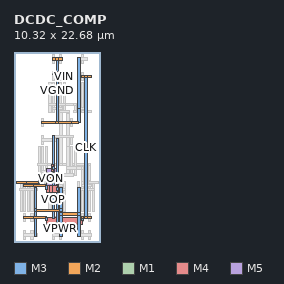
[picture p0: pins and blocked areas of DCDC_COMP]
MACRO DCDC_COMP
  ORIGIN 0 0 ;
  FOREIGN DCDC_COMP 0 0 ;
  SIZE 10.32 BY 22.68 ;
  PIN VOP
    DIRECTION INOUT ;
    USE SIGNAL ;
    PORT
      LAYER M3 ;
        RECT 4.59 2.78 4.87 7.3 ;
      LAYER M2 ;
        RECT 0.26 7 1.46 7.28 ;
      LAYER M3 ;
        RECT 5.02 7.82 5.3 12.34 ;
      LAYER M3 ;
        RECT 4.59 7.14 4.87 7.56 ;
      LAYER M2 ;
        RECT 3.01 7.42 4.73 7.7 ;
      LAYER M1 ;
        RECT 2.885 7.14 3.135 7.56 ;
      LAYER M2 ;
        RECT 1.29 7 3.01 7.28 ;
      LAYER M3 ;
        RECT 4.59 7.375 4.87 7.745 ;
      LAYER M4 ;
        RECT 4.73 7.16 5.16 7.96 ;
      LAYER M3 ;
        RECT 5.02 7.56 5.3 7.98 ;
    END
  END VOP
  PIN VON
    DIRECTION INOUT ;
    USE SIGNAL ;
    PORT
      LAYER M3 ;
        RECT 5.02 2.36 5.3 6.88 ;
      LAYER M2 ;
        RECT 1.12 6.58 2.32 6.86 ;
      LAYER M3 ;
        RECT 4.59 8.24 4.87 12.76 ;
      LAYER M3 ;
        RECT 5.02 6.115 5.3 6.485 ;
      LAYER M4 ;
        RECT 3.87 5.9 5.16 6.7 ;
      LAYER M3 ;
        RECT 3.73 6.3 4.01 6.72 ;
      LAYER M2 ;
        RECT 2.15 6.58 3.87 6.86 ;
      LAYER M4 ;
        RECT 4.275 5.9 4.605 6.7 ;
      LAYER M5 ;
        RECT 3.85 6.3 5.03 8.82 ;
      LAYER M4 ;
        RECT 4.435 8.42 4.735 9.22 ;
      LAYER M3 ;
        RECT 4.59 8.635 4.87 9.005 ;
    END
  END VON
  PIN VPWR
    DIRECTION INOUT ;
    USE SIGNAL ;
    PORT
      LAYER M3 ;
        RECT 5.45 0.68 5.73 6.46 ;
      LAYER M3 ;
        RECT 7.6 0.68 7.88 6.46 ;
      LAYER M3 ;
        RECT 2.44 0.68 2.72 6.46 ;
      LAYER M3 ;
        RECT 5.45 3.175 5.73 3.545 ;
      LAYER M2 ;
        RECT 5.59 3.22 7.74 3.5 ;
      LAYER M3 ;
        RECT 7.6 3.175 7.88 3.545 ;
      LAYER M3 ;
        RECT 5.45 3.595 5.73 3.965 ;
      LAYER M2 ;
        RECT 2.58 3.64 5.59 3.92 ;
      LAYER M3 ;
        RECT 2.44 3.595 2.72 3.965 ;
    END
  END VPWR
  PIN CLK
    DIRECTION INOUT ;
    USE SIGNAL ;
    PORT
      LAYER M2 ;
        RECT 8 2.8 9.2 3.08 ;
      LAYER M2 ;
        RECT 1.12 2.8 2.32 3.08 ;
      LAYER M2 ;
        RECT 8 19.6 9.2 19.88 ;
      LAYER M2 ;
        RECT 8.01 2.8 8.33 3.08 ;
      LAYER M3 ;
        RECT 8.03 2.52 8.31 2.94 ;
      LAYER M4 ;
        RECT 3.87 2.12 8.17 2.92 ;
      LAYER M3 ;
        RECT 3.73 2.52 4.01 2.94 ;
      LAYER M2 ;
        RECT 2.15 2.8 3.87 3.08 ;
      LAYER M2 ;
        RECT 8.44 2.8 8.76 3.08 ;
      LAYER M3 ;
        RECT 8.46 2.94 8.74 19.74 ;
      LAYER M2 ;
        RECT 8.44 19.6 8.76 19.88 ;
    END
  END CLK
  PIN VGND
    DIRECTION INOUT ;
    USE SIGNAL ;
    PORT
      LAYER M2 ;
        RECT 3.27 14.14 7.05 14.42 ;
      LAYER M2 ;
        RECT 4.56 21.7 5.76 21.98 ;
      LAYER M3 ;
        RECT 7.6 15.8 7.88 22 ;
      LAYER M2 ;
        RECT 5 14.14 5.32 14.42 ;
      LAYER M3 ;
        RECT 5.02 14.28 5.3 21.84 ;
      LAYER M2 ;
        RECT 5 21.7 5.32 21.98 ;
      LAYER M2 ;
        RECT 6.88 14.14 7.74 14.42 ;
      LAYER M3 ;
        RECT 7.6 14.28 7.88 15.96 ;
    END
  END VGND
  PIN VIN
    DIRECTION INOUT ;
    USE SIGNAL ;
    PORT
      LAYER M2 ;
        RECT 5.42 19.6 6.62 19.88 ;
    END
  END VIN
  PIN VIP
    DIRECTION INOUT ;
    USE SIGNAL ;
    PORT
      LAYER M2 ;
        RECT 4.56 20.02 5.76 20.3 ;
    END
  END VIP
  OBS
  LAYER M2 ;
        RECT 8.86 7 10.06 7.28 ;
  LAYER M2 ;
        RECT 2.84 9.1 4.04 9.38 ;
  LAYER M2 ;
        RECT 4.56 15.82 5.76 16.1 ;
  LAYER M2 ;
        RECT 8.87 7 9.19 7.28 ;
  LAYER M3 ;
        RECT 8.89 7.14 9.17 9.24 ;
  LAYER M2 ;
        RECT 3.87 9.1 9.03 9.38 ;
  LAYER M2 ;
        RECT 5.43 9.1 5.75 9.38 ;
  LAYER M3 ;
        RECT 5.45 9.24 5.73 15.96 ;
  LAYER M2 ;
        RECT 5.43 15.82 5.75 16.1 ;
  LAYER M2 ;
        RECT 8.87 7 9.19 7.28 ;
  LAYER M3 ;
        RECT 8.89 6.98 9.17 7.3 ;
  LAYER M2 ;
        RECT 8.87 9.1 9.19 9.38 ;
  LAYER M3 ;
        RECT 8.89 9.08 9.17 9.4 ;
  LAYER M2 ;
        RECT 8.87 7 9.19 7.28 ;
  LAYER M3 ;
        RECT 8.89 6.98 9.17 7.3 ;
  LAYER M2 ;
        RECT 8.87 9.1 9.19 9.38 ;
  LAYER M3 ;
        RECT 8.89 9.08 9.17 9.4 ;
  LAYER M2 ;
        RECT 5.43 9.1 5.75 9.38 ;
  LAYER M3 ;
        RECT 5.45 9.08 5.73 9.4 ;
  LAYER M2 ;
        RECT 5.43 15.82 5.75 16.1 ;
  LAYER M3 ;
        RECT 5.45 15.8 5.73 16.12 ;
  LAYER M2 ;
        RECT 8.87 7 9.19 7.28 ;
  LAYER M3 ;
        RECT 8.89 6.98 9.17 7.3 ;
  LAYER M2 ;
        RECT 8.87 9.1 9.19 9.38 ;
  LAYER M3 ;
        RECT 8.89 9.08 9.17 9.4 ;
  LAYER M2 ;
        RECT 5.43 9.1 5.75 9.38 ;
  LAYER M3 ;
        RECT 5.45 9.08 5.73 9.4 ;
  LAYER M2 ;
        RECT 5.43 15.82 5.75 16.1 ;
  LAYER M3 ;
        RECT 5.45 15.8 5.73 16.12 ;
  LAYER M2 ;
        RECT 8.87 7 9.19 7.28 ;
  LAYER M3 ;
        RECT 8.89 6.98 9.17 7.3 ;
  LAYER M2 ;
        RECT 8.87 9.1 9.19 9.38 ;
  LAYER M3 ;
        RECT 8.89 9.08 9.17 9.4 ;
  LAYER M2 ;
        RECT 8 6.58 9.2 6.86 ;
  LAYER M2 ;
        RECT 6.28 8.68 7.48 8.96 ;
  LAYER M2 ;
        RECT 5.42 15.4 6.62 15.68 ;
  LAYER M2 ;
        RECT 8.01 6.58 8.33 6.86 ;
  LAYER M3 ;
        RECT 8.03 6.72 8.31 8.82 ;
  LAYER M2 ;
        RECT 7.31 8.68 8.17 8.96 ;
  LAYER M2 ;
        RECT 6.29 8.68 6.61 8.96 ;
  LAYER M3 ;
        RECT 6.31 8.82 6.59 15.54 ;
  LAYER M2 ;
        RECT 6.29 15.4 6.61 15.68 ;
  LAYER M2 ;
        RECT 8.01 6.58 8.33 6.86 ;
  LAYER M3 ;
        RECT 8.03 6.56 8.31 6.88 ;
  LAYER M2 ;
        RECT 8.01 8.68 8.33 8.96 ;
  LAYER M3 ;
        RECT 8.03 8.66 8.31 8.98 ;
  LAYER M2 ;
        RECT 8.01 6.58 8.33 6.86 ;
  LAYER M3 ;
        RECT 8.03 6.56 8.31 6.88 ;
  LAYER M2 ;
        RECT 8.01 8.68 8.33 8.96 ;
  LAYER M3 ;
        RECT 8.03 8.66 8.31 8.98 ;
  LAYER M2 ;
        RECT 6.29 8.68 6.61 8.96 ;
  LAYER M3 ;
        RECT 6.31 8.66 6.59 8.98 ;
  LAYER M2 ;
        RECT 6.29 15.4 6.61 15.68 ;
  LAYER M3 ;
        RECT 6.31 15.38 6.59 15.7 ;
  LAYER M2 ;
        RECT 8.01 6.58 8.33 6.86 ;
  LAYER M3 ;
        RECT 8.03 6.56 8.31 6.88 ;
  LAYER M2 ;
        RECT 8.01 8.68 8.33 8.96 ;
  LAYER M3 ;
        RECT 8.03 8.66 8.31 8.98 ;
  LAYER M2 ;
        RECT 6.29 8.68 6.61 8.96 ;
  LAYER M3 ;
        RECT 6.31 8.66 6.59 8.98 ;
  LAYER M2 ;
        RECT 6.29 15.4 6.61 15.68 ;
  LAYER M3 ;
        RECT 6.31 15.38 6.59 15.7 ;
  LAYER M2 ;
        RECT 8.01 6.58 8.33 6.86 ;
  LAYER M3 ;
        RECT 8.03 6.56 8.31 6.88 ;
  LAYER M2 ;
        RECT 8.01 8.68 8.33 8.96 ;
  LAYER M3 ;
        RECT 8.03 8.66 8.31 8.98 ;
  LAYER M2 ;
        RECT 4.13 16.24 6.19 16.52 ;
  LAYER M2 ;
        RECT 8 15.4 9.2 15.68 ;
  LAYER M2 ;
        RECT 6.02 16.24 7.31 16.52 ;
  LAYER M1 ;
        RECT 7.185 15.54 7.435 16.38 ;
  LAYER M2 ;
        RECT 7.31 15.4 8.17 15.68 ;
  LAYER M1 ;
        RECT 7.185 15.455 7.435 15.625 ;
  LAYER M2 ;
        RECT 7.14 15.4 7.48 15.68 ;
  LAYER M1 ;
        RECT 7.185 16.295 7.435 16.465 ;
  LAYER M2 ;
        RECT 7.14 16.24 7.48 16.52 ;
  LAYER M1 ;
        RECT 7.185 15.455 7.435 15.625 ;
  LAYER M2 ;
        RECT 7.14 15.4 7.48 15.68 ;
  LAYER M1 ;
        RECT 7.185 16.295 7.435 16.465 ;
  LAYER M2 ;
        RECT 7.14 16.24 7.48 16.52 ;
  LAYER M1 ;
        RECT 4.605 3.695 4.855 7.225 ;
  LAYER M1 ;
        RECT 4.605 2.435 4.855 3.445 ;
  LAYER M1 ;
        RECT 4.605 0.335 4.855 1.345 ;
  LAYER M1 ;
        RECT 4.175 3.695 4.425 7.225 ;
  LAYER M1 ;
        RECT 5.035 3.695 5.285 7.225 ;
  LAYER M1 ;
        RECT 5.465 3.695 5.715 7.225 ;
  LAYER M1 ;
        RECT 5.465 2.435 5.715 3.445 ;
  LAYER M1 ;
        RECT 5.465 0.335 5.715 1.345 ;
  LAYER M1 ;
        RECT 5.895 3.695 6.145 7.225 ;
  LAYER M2 ;
        RECT 3.7 7 4.9 7.28 ;
  LAYER M2 ;
        RECT 4.56 2.8 5.76 3.08 ;
  LAYER M2 ;
        RECT 4.56 6.58 5.76 6.86 ;
  LAYER M2 ;
        RECT 4.13 2.38 5.33 2.66 ;
  LAYER M2 ;
        RECT 4.56 0.7 5.76 0.98 ;
  LAYER M2 ;
        RECT 4.13 6.16 6.19 6.44 ;
  LAYER M3 ;
        RECT 4.59 2.78 4.87 7.3 ;
  LAYER M3 ;
        RECT 5.02 2.36 5.3 6.88 ;
  LAYER M3 ;
        RECT 5.45 0.68 5.73 6.46 ;
  LAYER M1 ;
        RECT 8.905 3.695 9.155 7.225 ;
  LAYER M1 ;
        RECT 8.905 2.435 9.155 3.445 ;
  LAYER M1 ;
        RECT 8.905 0.335 9.155 1.345 ;
  LAYER M1 ;
        RECT 9.335 3.695 9.585 7.225 ;
  LAYER M1 ;
        RECT 8.475 3.695 8.725 7.225 ;
  LAYER M1 ;
        RECT 8.045 3.695 8.295 7.225 ;
  LAYER M1 ;
        RECT 8.045 2.435 8.295 3.445 ;
  LAYER M1 ;
        RECT 8.045 0.335 8.295 1.345 ;
  LAYER M1 ;
        RECT 7.615 3.695 7.865 7.225 ;
  LAYER M2 ;
        RECT 7.57 0.7 9.2 0.98 ;
  LAYER M2 ;
        RECT 7.57 6.16 9.63 6.44 ;
  LAYER M2 ;
        RECT 8.86 7 10.06 7.28 ;
  LAYER M2 ;
        RECT 8 6.58 9.2 6.86 ;
  LAYER M2 ;
        RECT 8 2.8 9.2 3.08 ;
  LAYER M3 ;
        RECT 7.6 0.68 7.88 6.46 ;
  LAYER M1 ;
        RECT 1.165 3.695 1.415 7.225 ;
  LAYER M1 ;
        RECT 1.165 2.435 1.415 3.445 ;
  LAYER M1 ;
        RECT 1.165 0.335 1.415 1.345 ;
  LAYER M1 ;
        RECT 0.735 3.695 0.985 7.225 ;
  LAYER M1 ;
        RECT 1.595 3.695 1.845 7.225 ;
  LAYER M1 ;
        RECT 2.025 3.695 2.275 7.225 ;
  LAYER M1 ;
        RECT 2.025 2.435 2.275 3.445 ;
  LAYER M1 ;
        RECT 2.025 0.335 2.275 1.345 ;
  LAYER M1 ;
        RECT 2.455 3.695 2.705 7.225 ;
  LAYER M2 ;
        RECT 1.12 0.7 2.75 0.98 ;
  LAYER M2 ;
        RECT 0.69 6.16 2.75 6.44 ;
  LAYER M2 ;
        RECT 0.26 7 1.46 7.28 ;
  LAYER M2 ;
        RECT 1.12 6.58 2.32 6.86 ;
  LAYER M2 ;
        RECT 1.12 2.8 2.32 3.08 ;
  LAYER M3 ;
        RECT 2.44 0.68 2.72 6.46 ;
  LAYER M1 ;
        RECT 6.755 7.895 7.005 11.425 ;
  LAYER M1 ;
        RECT 6.755 11.675 7.005 12.685 ;
  LAYER M1 ;
        RECT 6.755 13.775 7.005 14.785 ;
  LAYER M1 ;
        RECT 7.185 7.895 7.435 11.425 ;
  LAYER M1 ;
        RECT 6.325 7.895 6.575 11.425 ;
  LAYER M1 ;
        RECT 3.315 7.895 3.565 11.425 ;
  LAYER M1 ;
        RECT 3.315 11.675 3.565 12.685 ;
  LAYER M1 ;
        RECT 3.315 13.775 3.565 14.785 ;
  LAYER M1 ;
        RECT 3.745 7.895 3.995 11.425 ;
  LAYER M1 ;
        RECT 2.885 7.895 3.135 11.425 ;
  LAYER M2 ;
        RECT 4.99 7.84 7.05 8.12 ;
  LAYER M2 ;
        RECT 3.27 12.04 5.33 12.32 ;
  LAYER M2 ;
        RECT 3.27 8.26 4.9 8.54 ;
  LAYER M2 ;
        RECT 4.56 12.46 7.05 12.74 ;
  LAYER M2 ;
        RECT 3.27 14.14 7.05 14.42 ;
  LAYER M3 ;
        RECT 5.02 7.82 5.3 12.34 ;
  LAYER M3 ;
        RECT 4.59 8.24 4.87 12.76 ;
  LAYER M2 ;
        RECT 6.28 8.68 7.48 8.96 ;
  LAYER M2 ;
        RECT 2.84 9.1 4.04 9.38 ;
  LAYER M1 ;
        RECT 5.465 15.455 5.715 18.985 ;
  LAYER M1 ;
        RECT 5.465 19.235 5.715 20.245 ;
  LAYER M1 ;
        RECT 5.465 21.335 5.715 22.345 ;
  LAYER M1 ;
        RECT 5.895 15.455 6.145 18.985 ;
  LAYER M1 ;
        RECT 5.035 15.455 5.285 18.985 ;
  LAYER M1 ;
        RECT 4.605 15.455 4.855 18.985 ;
  LAYER M1 ;
        RECT 4.605 19.235 4.855 20.245 ;
  LAYER M1 ;
        RECT 4.605 21.335 4.855 22.345 ;
  LAYER M1 ;
        RECT 4.175 15.455 4.425 18.985 ;
  LAYER M2 ;
        RECT 4.56 21.7 5.76 21.98 ;
  LAYER M2 ;
        RECT 5.42 15.4 6.62 15.68 ;
  LAYER M2 ;
        RECT 4.56 15.82 5.76 16.1 ;
  LAYER M2 ;
        RECT 5.42 19.6 6.62 19.88 ;
  LAYER M2 ;
        RECT 4.56 20.02 5.76 20.3 ;
  LAYER M2 ;
        RECT 4.13 16.24 6.19 16.52 ;
  LAYER M1 ;
        RECT 8.045 15.455 8.295 18.985 ;
  LAYER M1 ;
        RECT 8.045 19.235 8.295 20.245 ;
  LAYER M1 ;
        RECT 8.045 21.335 8.295 22.345 ;
  LAYER M1 ;
        RECT 8.475 15.455 8.725 18.985 ;
  LAYER M1 ;
        RECT 7.615 15.455 7.865 18.985 ;
  LAYER M2 ;
        RECT 7.57 21.7 8.77 21.98 ;
  LAYER M2 ;
        RECT 7.57 15.82 8.77 16.1 ;
  LAYER M2 ;
        RECT 8 15.4 9.2 15.68 ;
  LAYER M2 ;
        RECT 8 19.6 9.2 19.88 ;
  LAYER M3 ;
        RECT 7.6 15.8 7.88 22 ;
  END
END DCDC_COMP
